One B-rep face of a CAD part: STEP entity #345.
In plain terms, the planar face has unit normal (1, 0, 0).
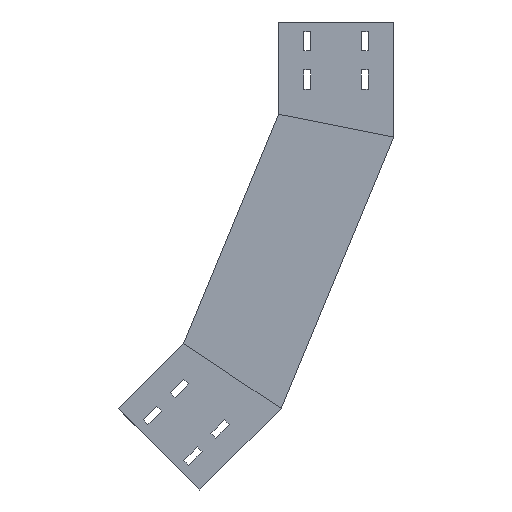
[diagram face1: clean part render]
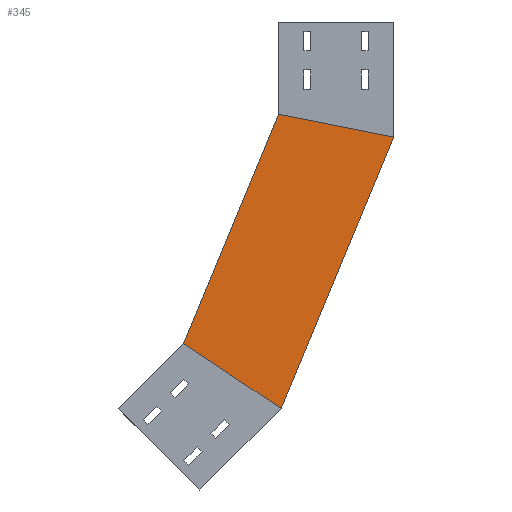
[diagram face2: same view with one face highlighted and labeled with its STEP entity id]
Its self-contained STEP definition (entity closure, numbers rounded to 3 decimals):
#43 = VECTOR ( 'NONE', #1552, 1000. ) ;
#46 = EDGE_LOOP ( 'NONE', ( #339, #1386, #47, #1908 ) ) ;
#47 = ORIENTED_EDGE ( 'NONE', *, *, #1556, .T. ) ;
#162 = EDGE_CURVE ( 'NONE', #743, #1702, #1606, .T. ) ;
#264 = DIRECTION ( 'NONE',  ( -1., 0., 0. ) ) ;
#339 = ORIENTED_EDGE ( 'NONE', *, *, #1224, .F. ) ;
#345 = ADVANCED_FACE ( 'NONE', ( #571 ), #1200, .F. ) ;
#363 = LINE ( 'NONE', #976, #1391 ) ;
#394 = EDGE_CURVE ( 'NONE', #878, #1454, #645, .T. ) ;
#418 = CARTESIAN_POINT ( 'NONE',  ( 0., 146.568, -503.846 ) ) ;
#571 = FACE_OUTER_BOUND ( 'NONE', #46, .T. ) ;
#628 = VECTOR ( 'NONE', #1235, 1000. ) ;
#645 = LINE ( 'NONE', #1423, #43 ) ;
#743 = VERTEX_POINT ( 'NONE', #1380 ) ;
#878 = VERTEX_POINT ( 'NONE', #1593 ) ;
#976 = CARTESIAN_POINT ( 'NONE',  ( 0., 138.582, -92.597 ) ) ;
#1033 = AXIS2_PLACEMENT_3D ( 'NONE', #1067, #264, #1046 ) ;
#1046 = DIRECTION ( 'NONE',  ( 0., 0., 1. ) ) ;
#1067 = CARTESIAN_POINT ( 'NONE',  ( 0., 0., -150. ) ) ;
#1200 = PLANE ( 'NONE',  #1033 ) ;
#1224 = EDGE_CURVE ( 'NONE', #878, #743, #363, .T. ) ;
#1235 = DIRECTION ( 'NONE',  ( 0., 0.383, -0.924 ) ) ;
#1380 = CARTESIAN_POINT ( 'NONE',  ( 0., 273.732, -418.878 ) ) ;
#1386 = ORIENTED_EDGE ( 'NONE', *, *, #394, .T. ) ;
#1391 = VECTOR ( 'NONE', #1755, 1000. ) ;
#1423 = CARTESIAN_POINT ( 'NONE',  ( 0., 28.701, -144.291 ) ) ;
#1454 = VERTEX_POINT ( 'NONE', #1810 ) ;
#1493 = CARTESIAN_POINT ( 'NONE',  ( 0., 208.695, -462.334 ) ) ;
#1552 = DIRECTION ( 'NONE',  ( 0., -0.981, -0.195 ) ) ;
#1556 = EDGE_CURVE ( 'NONE', #1454, #1702, #1558, .T. ) ;
#1558 = LINE ( 'NONE', #1838, #628 ) ;
#1593 = CARTESIAN_POINT ( 'NONE',  ( 0., 150., -120.163 ) ) ;
#1606 = LINE ( 'NONE', #1493, #1759 ) ;
#1702 = VERTEX_POINT ( 'NONE', #418 ) ;
#1755 = DIRECTION ( 'NONE',  ( 0., 0.383, -0.924 ) ) ;
#1759 = VECTOR ( 'NONE', #1800, 1000. ) ;
#1800 = DIRECTION ( 'NONE',  ( 0., -0.831, -0.556 ) ) ;
#1810 = CARTESIAN_POINT ( 'NONE',  ( 0., 0., -150. ) ) ;
#1838 = CARTESIAN_POINT ( 'NONE',  ( 0., 0., -150. ) ) ;
#1908 = ORIENTED_EDGE ( 'NONE', *, *, #162, .F. ) ;
